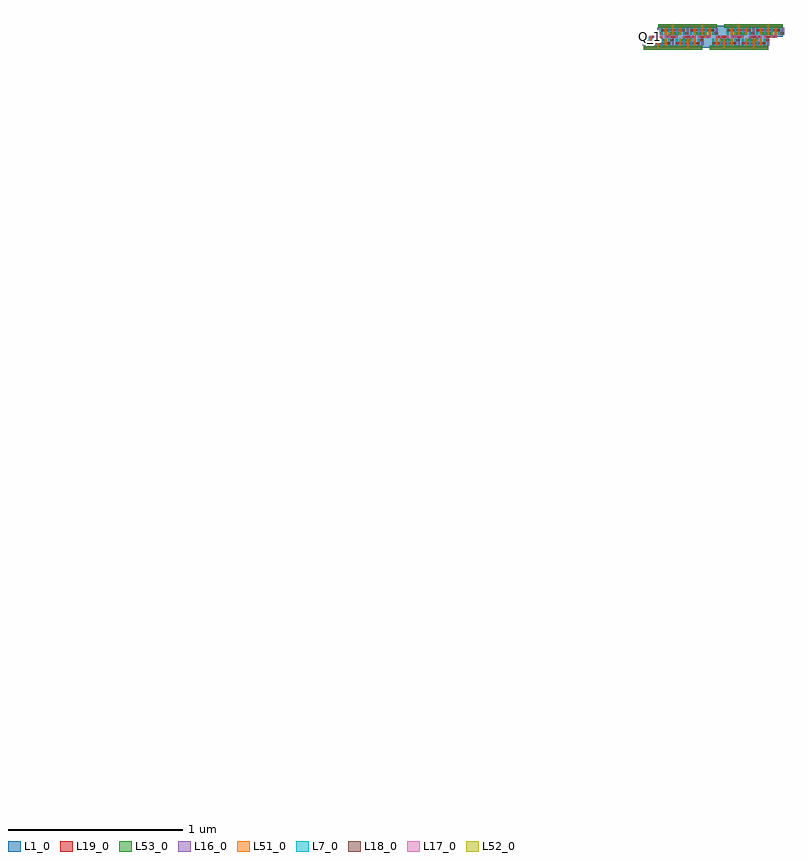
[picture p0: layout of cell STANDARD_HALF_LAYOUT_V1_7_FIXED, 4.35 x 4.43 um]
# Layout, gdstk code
import gdstk
lib = gdstk.Library(unit=1e-6, precision=1e-09)
def R(c, l, rs):  # rectangles x0, y0, x1, y1
    for r in rs: c.add(gdstk.rectangle(r[:2], r[2:], *l))
def A(c, l, x, y, w, h, nx, ny, dx, dy):  # array of equal rectangles
    R(c, l, [(x+i*dx, y+j*dy, x+i*dx+w, y+j*dy+h) for i in range(nx) for j in range(ny)])
def P(c, l, *ps):  # polygons
    for p in ps: c.add(gdstk.Polygon(p, *l))
L1_0 = (1, 0)
L7_0 = (7, 0)
L16_0 = (16, 0)
L17_0 = (17, 0)
L18_0 = (18, 0)
L19_0 = (19, 0)
L51_0 = (51, 0)
L52_0 = (52, 0)
L53_0 = (53, 0)

standard_half_layout_v1_ = lib.new_cell('STANDARD_HALF_LAYOUT_V1_7_FIXED')
A(standard_half_layout_v1_, L1_0, 0, 0, 0.042, 0.062, 17, 1, 0.042, 0)
A(standard_half_layout_v1_, L1_0, 0.084, 0.062, 0.042, 0.062, 17, 1, 0.042, 0)
P(standard_half_layout_v1_, L1_0, [(-2.637,-3.867),(-2.637,-3.867),(-2.637,-3.867),(-2.637,-3.867)],
  [(-3.548,-4.293),(-3.548,-4.293),(-3.548,-4.293),(-3.548,-4.293)],
  [(0.151,-0.013),(0.151,-0.013),(0.151,-0.013),(0.151,-0.013)],
  [(0.235,0.137),(0.235,0.137),(0.235,0.137),(0.235,0.137)],
  [(0.185,-0.013),(0.185,-0.013),(0.185,-0.013),(0.185,-0.013)],
  [(0.269,0.137),(0.269,0.137),(0.269,0.137),(0.269,0.137)],
  [(0.529,-0.013),(0.529,-0.013),(0.529,-0.013),(0.529,-0.013)],
  [(0.613,0.137),(0.613,0.137),(0.613,0.137),(0.613,0.137)],
  [(0.563,-0.013),(0.563,-0.013),(0.563,-0.013),(0.563,-0.013)],
  [(0.647,0.137),(0.647,0.137),(0.647,0.137),(0.647,0.137)])
A(standard_half_layout_v1_, L7_0, 0.015, 0.011, 0.012, 0.04, 8, 1, 0.042, 0)
A(standard_half_layout_v1_, L7_0, 0.393, 0.011, 0.012, 0.04, 8, 1, 0.042, 0)
A(standard_half_layout_v1_, L7_0, 0.099, 0.073, 0.012, 0.04, 8, 1, 0.042, 0)
A(standard_half_layout_v1_, L7_0, 0.477, 0.073, 0.012, 0.04, 8, 1, 0.042, 0)
A(standard_half_layout_v1_, L16_0, 0.12, 0.011, 0.012, 0.04, 3, 1, 0.042, 0)
A(standard_half_layout_v1_, L16_0, 0.498, 0.011, 0.012, 0.04, 3, 1, 0.042, 0)
A(standard_half_layout_v1_, L16_0, 0.204, 0.073, 0.012, 0.04, 3, 1, 0.042, 0)
A(standard_half_layout_v1_, L16_0, 0.582, 0.073, 0.012, 0.04, 3, 1, 0.042, 0)
R(standard_half_layout_v1_, L16_0, [(0.078,-0.006,0.09,0.051), (0.246,-0.006,0.258,0.051), (0.456,-0.006,0.468,0.051), (0.624,-0.006,0.636,0.051), (-0.006,0.011,0.006,0.051), (0.036,0.011,0.048,0.068), (0.057,0.011,0.069,0.068), (0.099,0.011,0.111,0.068), (0.225,0.011,0.237,0.068), (0.267,0.011,0.279,0.068), (0.288,0.011,0.3,0.068), (0.33,0.011,0.342,0.051), (0.414,0.011,0.426,0.068), (0.435,0.011,0.447,0.068), (0.477,0.011,0.489,0.068), (0.603,0.011,0.615,0.068), (0.645,0.011,0.657,0.068), (0.666,0.011,0.678,0.068), (0.708,0.011,0.72,0.051), (0.12,0.056,0.132,0.113), (0.141,0.056,0.153,0.113), (0.183,0.056,0.195,0.113), (0.309,0.056,0.321,0.113), (0.351,0.056,0.363,0.113), (0.372,0.056,0.384,0.113), (0.498,0.056,0.51,0.113), (0.519,0.056,0.531,0.113), (0.561,0.056,0.573,0.113), (0.687,0.056,0.699,0.113), (0.729,0.056,0.741,0.113), (0.75,0.056,0.762,0.113), (0.078,0.073,0.09,0.113), (0.162,0.073,0.174,0.13), (0.33,0.073,0.342,0.13), (0.413,0.073,0.425,0.113), (0.54,0.073,0.552,0.13), (0.708,0.073,0.72,0.13), (0.792,0.073,0.804,0.113)])
R(standard_half_layout_v1_, L17_0, [(0.036,0.056,0.048,0.068), (0.057,0.056,0.069,0.068), (0.099,0.056,0.111,0.068), (0.121,0.056,0.133,0.068), (0.142,0.056,0.154,0.068), (0.184,0.056,0.196,0.068), (0.225,0.056,0.237,0.068), (0.267,0.056,0.279,0.068), (0.288,0.056,0.3,0.068), (0.31,0.056,0.322,0.068), (0.352,0.056,0.364,0.068), (0.373,0.056,0.385,0.068), (0.414,0.056,0.426,0.068), (0.435,0.056,0.447,0.068), (0.477,0.056,0.489,0.068), (0.499,0.056,0.511,0.068), (0.52,0.056,0.532,0.068), (0.562,0.056,0.574,0.068), (0.603,0.056,0.615,0.068), (0.645,0.056,0.657,0.068), (0.666,0.056,0.678,0.068), (0.688,0.056,0.7,0.068), (0.73,0.056,0.742,0.068), (0.751,0.056,0.763,0.068)])
A(standard_half_layout_v1_, L18_0, -0.005, 0.038, 0.01, 0.01, 3, 1, 0.063, 0)
A(standard_half_layout_v1_, L18_0, 0.205, 0.038, 0.01, 0.01, 3, 1, 0.063, 0)
A(standard_half_layout_v1_, L18_0, 0.499, 0.038, 0.01, 0.01, 3, 1, 0.042, 0)
A(standard_half_layout_v1_, L18_0, 0.079, 0.076, 0.01, 0.01, 3, 1, 0.063, 0)
A(standard_half_layout_v1_, L18_0, 0.583, 0.076, 0.01, 0.01, 3, 1, 0.042, 0)
R(standard_half_layout_v1_, L18_0, [(0.079,-0.005,0.089,0.005), (0.247,-0.005,0.257,0.005), (0.457,-0.005,0.467,0.005), (0.625,-0.005,0.635,0.005), (0.016,0.02,0.026,0.03), (0.142,0.02,0.152,0.03), (0.184,0.02,0.194,0.03), (0.31,0.02,0.32,0.03), (0.394,0.02,0.404,0.03), (0.52,0.02,0.53,0.03), (0.562,0.02,0.572,0.03), (0.688,0.02,0.698,0.03), (0.163,0.038,0.173,0.048), (0.436,0.038,0.446,0.048), (0.646,0.038,0.656,0.048), (0.709,0.038,0.719,0.048), (0.037,0.057,0.047,0.067), (0.1,0.057,0.11,0.067), (0.122,0.057,0.132,0.067), (0.185,0.057,0.195,0.067), (0.226,0.057,0.236,0.067), (0.289,0.057,0.299,0.067), (0.311,0.057,0.321,0.067), (0.374,0.057,0.384,0.067), (0.415,0.057,0.425,0.067), (0.478,0.057,0.488,0.067), (0.5,0.057,0.51,0.067), (0.563,0.057,0.573,0.067), (0.604,0.057,0.614,0.067), (0.667,0.057,0.677,0.067), (0.689,0.057,0.699,0.067), (0.752,0.057,0.762,0.067), (0.247,0.076,0.257,0.086), (0.289,0.076,0.299,0.086), (0.352,0.076,0.362,0.086), (0.414,0.076,0.424,0.086), (0.52,0.076,0.53,0.086), (0.73,0.076,0.74,0.086), (0.793,0.076,0.803,0.086), (0.1,0.094,0.11,0.104), (0.226,0.094,0.236,0.104), (0.268,0.094,0.278,0.104), (0.394,0.094,0.404,0.104), (0.478,0.094,0.488,0.104), (0.604,0.094,0.614,0.104), (0.646,0.094,0.656,0.104), (0.772,0.094,0.782,0.104), (0.163,0.119,0.173,0.129), (0.331,0.119,0.341,0.129), (0.541,0.119,0.551,0.129), (0.709,0.119,0.719,0.129)])
R(standard_half_layout_v1_, L19_0, [(0,-0.011,0.168,0.011), (0.168,-0.011,0.336,0.011), (0.378,-0.011,0.546,0.011), (0.546,-0.011,0.714,0.011), (0.015,0.02,0.153,0.03), (0.183,0.02,0.321,0.03), (0.393,0.02,0.531,0.03), (0.561,0.02,0.699,0.03), (-0.006,0.037,0.016,0.049), (0.057,0.037,0.132,0.049), (0.151,0.037,0.174,0.049), (0.204,0.037,0.279,0.049), (0.32,0.037,0.342,0.049), (0.435,0.037,0.51,0.049), (0.529,0.037,0.552,0.049), (0.582,0.037,0.657,0.049), (0.698,0.037,0.72,0.049), (0.036,0.056,0.111,0.068), (0.121,0.056,0.196,0.068), (0.225,0.056,0.3,0.068), (0.31,0.056,0.385,0.068), (0.414,0.056,0.489,0.068), (0.499,0.056,0.574,0.068), (0.603,0.056,0.678,0.068), (0.688,0.056,0.763,0.068), (0.078,0.075,0.1,0.087), (0.141,0.075,0.216,0.087), (0.235,0.075,0.258,0.087), (0.288,0.075,0.363,0.087), (0.403,0.075,0.425,0.087), (0.519,0.075,0.594,0.087), (0.613,0.075,0.636,0.087), (0.666,0.075,0.741,0.087), (0.782,0.075,0.804,0.087), (0.099,0.094,0.237,0.104), (0.267,0.094,0.405,0.104), (0.477,0.094,0.615,0.104), (0.645,0.094,0.783,0.104), (0.084,0.113,0.252,0.135), (0.252,0.113,0.42,0.135), (0.462,0.113,0.63,0.135), (0.63,0.113,0.798,0.135)])
R(standard_half_layout_v1_, L51_0, [(0.078,-0.006,0.09,0.051), (0.246,-0.006,0.258,0.051), (0.456,-0.006,0.468,0.051), (0.624,-0.006,0.636,0.051), (0.036,0.011,0.048,0.068), (0.057,0.011,0.069,0.068), (0.099,0.011,0.111,0.068), (0.12,0.011,0.132,0.051), (0.204,0.011,0.216,0.051), (0.225,0.011,0.237,0.068), (0.267,0.011,0.279,0.068), (0.288,0.011,0.3,0.068), (0.414,0.011,0.426,0.068), (0.435,0.011,0.447,0.068), (0.477,0.011,0.489,0.068), (0.498,0.011,0.51,0.051), (0.582,0.011,0.594,0.051), (0.603,0.011,0.615,0.068), (0.645,0.011,0.657,0.068), (0.666,0.011,0.678,0.068), (0.12,0.056,0.132,0.113), (0.141,0.056,0.153,0.113), (0.183,0.056,0.195,0.113), (0.309,0.056,0.321,0.113), (0.351,0.056,0.363,0.113), (0.372,0.056,0.384,0.113), (0.498,0.056,0.51,0.113), (0.519,0.056,0.531,0.113), (0.561,0.056,0.573,0.113), (0.687,0.056,0.699,0.113), (0.729,0.056,0.741,0.113), (0.75,0.056,0.762,0.113), (0.162,0.073,0.174,0.13), (0.204,0.073,0.216,0.113), (0.288,0.073,0.3,0.113), (0.33,0.073,0.342,0.13), (0.54,0.073,0.552,0.13), (0.582,0.073,0.594,0.113), (0.666,0.073,0.678,0.113), (0.708,0.073,0.72,0.13)])
R(standard_half_layout_v1_, L52_0, [(0.079,-0.005,0.089,0.005), (0.247,-0.005,0.257,0.005), (0.457,-0.005,0.467,0.005), (0.625,-0.005,0.635,0.005), (0.058,0.038,0.068,0.048), (0.121,0.038,0.131,0.048), (0.205,0.038,0.215,0.048), (0.268,0.038,0.278,0.048), (0.436,0.038,0.446,0.048), (0.499,0.038,0.509,0.048), (0.583,0.038,0.593,0.048), (0.646,0.038,0.656,0.048), (0.142,0.076,0.152,0.086), (0.205,0.076,0.215,0.086), (0.289,0.076,0.299,0.086), (0.352,0.076,0.362,0.086), (0.52,0.076,0.53,0.086), (0.583,0.076,0.593,0.086), (0.667,0.076,0.677,0.086), (0.73,0.076,0.74,0.086), (0.163,0.119,0.173,0.129), (0.331,0.119,0.341,0.129), (0.541,0.119,0.551,0.129), (0.709,0.119,0.719,0.129)])
R(standard_half_layout_v1_, L53_0, [(0,-0.011,0.168,0.011), (0.168,-0.011,0.336,0.011), (0.378,-0.011,0.546,0.011), (0.546,-0.011,0.714,0.011), (0.057,0.037,0.132,0.049), (0.204,0.037,0.279,0.049), (0.435,0.037,0.51,0.049), (0.582,0.037,0.657,0.049), (0.141,0.075,0.216,0.087), (0.288,0.075,0.363,0.087), (0.519,0.075,0.594,0.087), (0.666,0.075,0.741,0.087), (0.084,0.113,0.252,0.135), (0.252,0.113,0.42,0.135), (0.462,0.113,0.63,0.135), (0.63,0.113,0.798,0.135)])
standard_half_layout_v1_.add(gdstk.Label('Q_1', (0.042,0.062), layer=17, texttype=0))
standard_half_layout_v1_.add(gdstk.Label('QB_1', (0.105,0.062), layer=17, texttype=0))
standard_half_layout_v1_.add(gdstk.Label('WL_1', (0.084,0.025), layer=19, texttype=0))
standard_half_layout_v1_.add(gdstk.Label('BLB_1', (0.162,0.043), layer=19, texttype=0))
standard_half_layout_v1_.add(gdstk.Label('BL_1', (0.005,0.043), layer=19, texttype=0))
standard_half_layout_v1_.add(gdstk.Label('VSS_1', (0.084,0), layer=19, texttype=0))
standard_half_layout_v1_.add(gdstk.Label('VDD_1', (0.084,0), layer=53, texttype=0))
standard_half_layout_v1_.add(gdstk.Label('VDD_2', (0.168,0.124), layer=53, texttype=0))

lib.write_gds('STANDARD_HALF_LAYOUT_V1_7_FIXED.gds')
